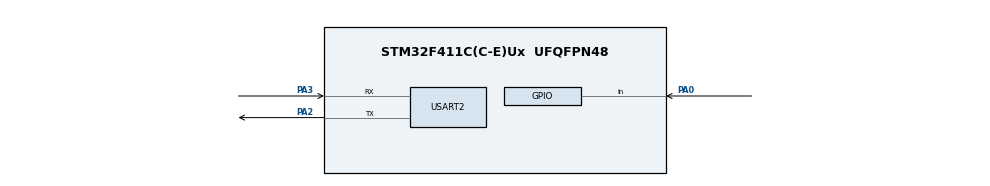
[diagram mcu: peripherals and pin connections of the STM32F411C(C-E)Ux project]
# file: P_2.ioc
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Mcu.Family=STM32F4
Mcu.Name=STM32F411C(C-E)Ux
Mcu.Package=UFQFPN48
NVIC.PriorityGroup=NVIC_PRIORITYGROUP_4
PA0-WKUP.GPIO_PuPd=GPIO_PULLUP
PA0-WKUP.Signal=GPIO_Input
PA13.Mode=Serial_Wire
PA13.Signal=SYS_JTMS-SWDIO
PA14.Mode=Serial_Wire
PA14.Signal=SYS_JTCK-SWCLK
PA2.Mode=Asynchronous
PA2.Signal=USART2_TX
PA3.Mode=Asynchronous
PA3.Signal=USART2_RX
ProjectManager.HeapSize=0x200
ProjectManager.StackSize=0x400
ProjectManager.TargetToolchain=STM32CubeIDE
RCC.AHBFreq_Value=16000000
RCC.APB1Freq_Value=16000000
RCC.APB2Freq_Value=16000000
RCC.CortexFreq_Value=16000000
RCC.HSE_VALUE=25000000
RCC.HSI_VALUE=16000000
RCC.LSE_VALUE=32768
RCC.SYSCLKFreq_VALUE=16000000
RCC.VCOOutputFreq_Value=192000000
USART2.VirtualMode=VM_ASYNC
VP_CRC_VS_CRC.Mode=CRC_Activate
board=custom

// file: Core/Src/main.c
/* USER CODE BEGIN Header */
/**
  ******************************************************************************
  * @file           : main.c
  * @brief          : Main program body
  ******************************************************************************
  * @attention
  *
  * Copyright (c) 2025 STMicroelectronics.
  * All rights reserved.
  *
  * This software is licensed under terms that can be found in the LICENSE file
  * in the root directory of this software component.
  * If no LICENSE file comes with this software, it is provided AS-IS.
  *
  ******************************************************************************
  */
/* USER CODE END Header */
#include "main.h"

CRC_HandleTypeDef hcrc;

UART_HandleTypeDef huart2;

/* USER CODE BEGIN PV */
#define C_UART			huart2

uint8_t bl_rx_buffer[200];
uint8_t supported_commands[10] = {BL_GET_VER, BL_GET_HELP, BL_GET_CID, BL_GET_RDP_STATUS, BL_GO_TO_ADDR,BL_FLASH_ERASE,
		BL_MEM_WRITE, BL_EN_RW_PROTECT, BL_MEM_READ, BL_READ_SECTOR_P_STATUS, BL_OTP_READ, BL_DIS_R_W_PROTECT};
/* USER CODE END PV */

void SystemClock_Config(void);
static void MX_GPIO_Init(void);
static void MX_USART2_UART_Init(void);
static void MX_CRC_Init(void);
/* USER CODE BEGIN PFP */
static void printmsg(char *format,...);
static void bootloader_send_ack(uint8_t command_code, uint8_t follow_len);
static void bootloader_send_nack(void);
uint8_t bootloader_verify_crc (uint8_t *pData, uint32_t len, uint32_t crc_host);
static uint8_t get_bootloader_version(void);
static void bootloader_uart_write_data(uint8_t *pBuffer,uint32_t len);
uint16_t get_mcu_device_id(void);
uint8_t get_flash_rdp_level(void);
uint8_t verify_addr(uint32_t addr);
uint8_t execute_flash_erase(uint8_t sector_number , uint8_t number_of_sector);
uint8_t program_memory(uint8_t *pBuffer, uint32_t base_mem_addr, uint8_t payload_length);
uint8_t configure_protection(uint8_t protection, uint8_t sector_detail, uint8_t disable);
void read_protection_status(uint8_t *sector_detail);
/* USER CODE END PFP */

int main(void)
{

  /* USER CODE BEGIN 1 */
#define BL_DEBUG_MSG_EN		1
  /* USER CODE END 1 */

  /* MCU Configuration--------------------------------------------------------*/

  /* Reset of all peripherals, Initializes the Flash interface and the Systick. */
  HAL_Init();

  /* Configure the system clock */
  SystemClock_Config();

  /* Initialize all configured peripherals */
  MX_GPIO_Init();
  MX_USART2_UART_Init();
  MX_CRC_Init();

  /* Infinite loop */
  while (1)
  {

    /* USER CODE BEGIN 3 */
	  if(HAL_GPIO_ReadPin(GPIOA, GPIO_PIN_0) == 1)
	    {
	  	  // button is pressed
	  	  printmsg("BL_DEBUG_MSG:Button is pressed .. going to BL mode \r\n");

	  	  bootloader_uart_read_data();
	    }
	    else
	    {
	  	printmsg("BL_DEBUG_MSG:Button is not pressed .. executing user app\r\n");
	  	 bootloader_jump_to_user_app();
	    }
  }
  /* USER CODE END 3 */
}

void SystemClock_Config(void)
{
    RCC_OscInitTypeDef RCC_OscInitStruct = {0};
    RCC_ClkInitTypeDef RCC_ClkInitStruct = {0};

    /** Configure the main internal regulator output voltage */
    __HAL_RCC_PWR_CLK_ENABLE();
    __HAL_PWR_VOLTAGESCALING_CONFIG(PWR_REGULATOR_VOLTAGE_SCALE1);

    /** Initializes the RCC Oscillators according to the specified parameters */
    RCC_OscInitStruct.OscillatorType = RCC_OSCILLATORTYPE_HSE;
    RCC_OscInitStruct.HSEState = RCC_HSE_ON;               // ✅ Enable external 25 MHz crystal
    RCC_OscInitStruct.PLL.PLLState = RCC_PLL_ON;           // ✅ Enable PLL
    RCC_OscInitStruct.PLL.PLLSource = RCC_PLLSOURCE_HSE;   // ✅ Source = HSE
    RCC_OscInitStruct.PLL.PLLM = 25;                       // Divide 25 MHz → 1 MHz
    RCC_OscInitStruct.PLL.PLLN = 100;                      // Multiply 1 MHz → 100 MHz
    RCC_OscInitStruct.PLL.PLLP = RCC_PLLP_DIV2;            // 100 MHz / 2 = 100 MHz SYSCLK
    RCC_OscInitStruct.PLL.PLLQ = 4;                        // Optional (USB clock etc.)

    if (HAL_RCC_OscConfig(&RCC_OscInitStruct) != HAL_OK)
    {
        Error_Handler();
    }

    /** Initializes the CPU, AHB and APB buses clocks */
    RCC_ClkInitStruct.ClockType = RCC_CLOCKTYPE_HCLK |
                                  RCC_CLOCKTYPE_SYSCLK |
                                  RCC_CLOCKTYPE_PCLK1 |
                                  RCC_CLOCKTYPE_PCLK2;

    RCC_ClkInitStruct.SYSCLKSource = RCC_SYSCLKSOURCE_PLLCLK;  // ✅ Use PLL as system clock
    RCC_ClkInitStruct.AHBCLKDivider = RCC_SYSCLK_DIV1;         // AHB = 100 MHz
    RCC_ClkInitStruct.APB1CLKDivider = RCC_HCLK_DIV2;          // APB1 = 50 MHz (max)
    RCC_ClkInitStruct.APB2CLKDivider = RCC_HCLK_DIV1;          // APB2 = 100 MHz

    if (HAL_RCC_ClockConfig(&RCC_ClkInitStruct, FLASH_LATENCY_3) != HAL_OK)
    {
        Error_Handler();
    }
}

static void MX_CRC_Init(void)
{

  hcrc.Instance = CRC;
  if (HAL_CRC_Init(&hcrc) != HAL_OK)
  {
    Error_Handler();
  }

}

static void MX_USART2_UART_Init(void)
{

  huart2.Instance = USART2;
  huart2.Init.BaudRate = 9600;
  huart2.Init.WordLength = UART_WORDLENGTH_8B;
  huart2.Init.StopBits = UART_STOPBITS_1;
  huart2.Init.Parity = UART_PARITY_NONE;
  huart2.Init.Mode = UART_MODE_TX_RX;
  huart2.Init.HwFlowCtl = UART_HWCONTROL_NONE;
  huart2.Init.OverSampling = UART_OVERSAMPLING_16;
  if (HAL_UART_Init(&huart2) != HAL_OK)
  {
    Error_Handler();
  }

}

static void MX_GPIO_Init(void)
{
  GPIO_InitTypeDef GPIO_InitStruct = {0};

  /* GPIO Ports Clock Enable */
  __HAL_RCC_GPIOA_CLK_ENABLE();

  /*Configure GPIO pin : PA0 */
  GPIO_InitStruct.Pin = GPIO_PIN_0;
  GPIO_InitStruct.Mode = GPIO_MODE_INPUT;
  GPIO_InitStruct.Pull = GPIO_PULLUP;
  HAL_GPIO_Init(GPIOA, &GPIO_InitStruct);

}

/* USER CODE BEGIN 4 */
static void printmsg(char *format,...)
{
#ifdef BL_DEBUG_MSG_EN
	char str[80];

	va_list args;
	va_start(args, format);
	vsprintf(str, format, args);
	printf(str);
	//HAL_UART_Transmit(&huart2, (uint8_t*)str, strlen(str), HAL_MAX_DELAY);
	va_end(args);
#endif
}

void bootloader_uart_read_data(void)
{
	uint8_t rcv_len;
	memset(bl_rx_buffer, 0, 200);

	HAL_UART_Receive(&C_UART, bl_rx_buffer, 1, HAL_MAX_DELAY);
	rcv_len = bl_rx_buffer[0];
	HAL_UART_Receive(&C_UART, &bl_rx_buffer[1], rcv_len, HAL_MAX_DELAY);
	switch(bl_rx_buffer[1])
	{
		 case BL_GET_VER:
	          bootloader_handle_getver_cmd(bl_rx_buffer);
	          break;
	      case BL_GET_HELP:
	          bootloader_handle_gethelp_cmd(bl_rx_buffer);
	          break;
	      case BL_GET_CID:
	          bootloader_handle_getcid_cmd(bl_rx_buffer);
	          break;
	      case BL_GET_RDP_STATUS:
	          bootloader_handle_getrdp_cmd(bl_rx_buffer);
	          break;
	      case BL_GO_TO_ADDR:
	          bootloader_handle_go_cmd(bl_rx_buffer);
	          break;
	      case BL_FLASH_ERASE:
	          bootloader_handle_flash_erase_cmd(bl_rx_buffer);
	          break;
	      case BL_MEM_WRITE:
	          bootloader_handle_mem_write_cmd(bl_rx_buffer);
	          break;
	      case BL_EN_RW_PROTECT:
	          bootloader_handle_en_rw_protect(bl_rx_buffer);
	          break;
	      case BL_MEM_READ:
	          bootloader_handle_mem_read(bl_rx_buffer);
	          break;
	      case BL_READ_SECTOR_P_STATUS:
	          bootloader_handle_read_sector_protection_status(bl_rx_buffer);
	          break;
	      case BL_OTP_READ:
	          bootloader_handle_read_otp(bl_rx_buffer);
	          break;
	      case BL_DIS_R_W_PROTECT:
	          bootloader_handle_dis_rw_protect(bl_rx_buffer);
	          break;
	       default:
	          printmsg("BL_DEBUG_MSG:Invalid command code received from host \n");
	          break;
	}

}

void bootloader_jump_to_user_app(void)
{

	__disable_irq();

	// Disable SysTick
	SysTick->CTRL = 0;
	SysTick->VAL  = 0;

	// Disable UART fully
	__HAL_UART_DISABLE(&huart2);
	USART2->CR1 = 0;
	USART2->CR2 = 0;
	USART2->CR3 = 0;
	USART2->SR  = 0;
	USART2->DR  = 0;

	// Disable UART NVIC line
	NVIC_DisableIRQ(USART2_IRQn);

	// Clear ALL pending interrupts
	for(int i = 0; i < 8; i++)
	    NVIC->ICPR[i] = 0xFFFFFFFF;

	// Load MSP
	__set_MSP(*(uint32_t*)FLASH_SECTOR2_BASE_ADDRESS);

	// Fix Thumb-bit
	uint32_t resetHandler = (*(uint32_t*)(FLASH_SECTOR2_BASE_ADDRESS + 4)) | 1;

	// Set VTOR
	SCB->VTOR = FLASH_SECTOR2_BASE_ADDRESS;

	__DSB();
	__ISB();

	__enable_irq();

	// Jump
	((void (*)(void))resetHandler)();

}

void HAL_GPIO_EXTI_Callback(uint16_t GPIO_Pin)
{
	printmsg("BL_DEBUG_MSG:Button is pressed .. going to BL mode \r\n");

}

void bootloader_handle_getver_cmd(uint8_t *bl_rx_buffer)
{
	uint8_t bl_version;
	//1. Verify the checksum(CRC)
	printmsg("BL_DEBUG_MSG:bootloader handler getver cmd\n");
	 // 1) verify the checksum
	  printmsg("BL_DEBUG_MSG:bootloader_handle_getver_cmd\n");

	  //Total length of the command packet
	  uint32_t command_packet_len = bl_rx_buffer[0]+1 ;

	  //extract the CRC32 sent by the Host
	  uint32_t host_crc = *((uint32_t * ) (bl_rx_buffer+command_packet_len - 4) ) ;

	if(! bootloader_verify_crc(&bl_rx_buffer[0], 2, host_crc))
	{
		printmsg("BL_DEBUG_MSG:checksum success !!\n");
		//checksum is correct..
		bootloader_send_ack(bl_rx_buffer[0],1);
		bl_version = get_bootloader_version();
		printmsg("BL_DEBUG_MSG:BL_VER: %d %#\n", bl_version, bl_version);
		bootloader_uart_write_data(&bl_version, 1);
	}else
	{
		printmsg("BL_DEBUS_MSG:checksum fail !!\n");
		//checksum is wrong send nack
		bootloader_send_nack();
	}

}
void bootloader_handle_gethelp_cmd(uint8_t *pBuffer)
{
	//1. Verify the checksum(CRC)
	printmsg("BL_DEBUG_MSG:bootloader handler gethelp cmd\n");
		//Total length of the command packet
	  uint32_t command_packet_len = bl_rx_buffer[0]+1 ;

	  //extract the CRC32 sent by the Host
	  uint32_t host_crc = *((uint32_t * ) (bl_rx_buffer+command_packet_len - 4) ) ;

	if(! bootloader_verify_crc(&pBuffer[0], 2, host_crc))
	{
		printmsg("BL_DEBUG_MSG:checksum success !!\n");
		//checksum is correct..
		bootloader_send_ack(bl_rx_buffer[0],sizeof(supported_commands));
		bootloader_uart_write_data(supported_commands, sizeof(supported_commands));
	}else
	{
		printmsg("BL_DEBUS_MSG:checksum fail !!\n");
		//checksum is wrong send nack
		bootloader_send_nack();
	}

}
void bootloader_handle_getcid_cmd(uint8_t *pBuffer)
{
	uint16_t cid = get_mcu_device_id();
	//1. Verify the checksum(CRC)
		printmsg("BL_DEBUG_MSG:bootloader handler getcid cmd\n");
			//Total length of the command packet
		  uint32_t command_packet_len = bl_rx_buffer[0]+1 ;

		  //extract the CRC32 sent by the Host
		  uint32_t host_crc = *((uint32_t * ) (bl_rx_buffer+command_packet_len - 4) ) ;

		if(! bootloader_verify_crc(&pBuffer[0], 2, host_crc))
		{
			printmsg("BL_DEBUG_MSG:checksum success !!\n");
			//checksum is correct..

			bootloader_send_ack(bl_rx_buffer[0],sizeof(cid));
			bootloader_uart_write_data((uint8_t*)&cid, 2);
		}else
		{
			printmsg("BL_DEBUS_MSG:checksum fail !!\n");
			//checksum is wrong send nack
			bootloader_send_nack();
		}

}
void bootloader_handle_getrdp_cmd(uint8_t *pBuffer)
{
	uint8_t rdp_status = get_flash_rdp_level();
	//1. Verify the checksum(CRC)
		printmsg("BL_DEBUG_MSG:bootloader handler getrdp cmd\n");
			//Total length of the command packet
		  uint32_t command_packet_len = bl_rx_buffer[0]+1 ;

		  //extract the CRC32 sent by the Host
		  uint32_t host_crc = *((uint32_t * ) (bl_rx_buffer+command_packet_len - 4) ) ;

		if(! bootloader_verify_crc(&pBuffer[0], 2, host_crc))
		{
			printmsg("BL_DEBUG_MSG:checksum success !!\n");
			//checksum is correct..

			bootloader_send_ack(bl_rx_buffer[0],sizeof(rdp_status));
			bootloader_uart_write_data((uint8_t*)&rdp_status, 1);
		}else
		{
			printmsg("BL_DEBUS_MSG:checksum fail !!\n");
			//checksum is wrong send nack
			bootloader_send_nack();
		}

}
void bootloader_handle_go_cmd(uint8_t *pBuffer)
{
	uint32_t go_addr = 0;
	uint8_t addr_valid = ADDR_VALID;
	uint8_t addr_invalid = ADDR_INVALID;
	//1. Verify the checksum(CRC)
		printmsg("BL_DEBUG_MSG:bootloader handler go_cmd cmd\n");
			//Total length of the command packet
		  uint32_t command_packet_len = bl_rx_buffer[0]+1 ;

		  //extract the CRC32 sent by the Host
		  uint32_t host_crc = *((uint32_t * ) (bl_rx_buffer+command_packet_len - 4) ) ;

		if(! bootloader_verify_crc(&pBuffer[0], command_packet_len - 4, host_crc))
		{
			printmsg("BL_DEBUG_MSG:checksum success !!\n");
			//checksum is correct..

			bootloader_send_ack(bl_rx_buffer[0],1);

			//etract the go address
			go_addr = *((uint32_t*)&pBuffer[2]);
			if(verify_addr(go_addr) == ADDR_VALID)
			{
				// tell host that address is find
				bootloader_uart_write_data(&addr_valid, 1);
				if(go_addr != 0x08008000)
				{
					go_addr += 1; // for T bit
					void(*lets_jump)(void) = (void*)go_addr;
					printmsg("BL_DEBUG_MSG: jumping to the address\n");
					lets_jump();
				}
				else
				{
					bootloader_jump_to_user_app();
				}

			}
			else
			{
				printmsg("BL_DEBUS_MSG: invalid address\n");
				bootloader_uart_write_data(&addr_invalid, 1);
			}

		}else
		{
			printmsg("BL_DEBUS_MSG:checksum fail !!\n");
			//checksum is wrong send nack
			bootloader_send_nack();
		}

}
void bootloader_handle_flash_erase_cmd(uint8_t *pBuffer)
{
	uint8_t sector_addr = 0;

	uint8_t no_of_sectors = 0;
	uint8_t erase_status = 0x00;
	//1. Verify the checksum(CRC)
		printmsg("BL_DEBUG_MSG:bootloader handler flash_erase_cmd\n");
			//Total length of the command packet
		  uint32_t command_packet_len = bl_rx_buffer[0]+1 ;

		  //extract the CRC32 sent by the Host
		  uint32_t host_crc = *((uint32_t * ) (bl_rx_buffer+command_packet_len - 4) ) ;

		if(! bootloader_verify_crc(&pBuffer[0], command_packet_len - 4, host_crc))
		{
			printmsg("BL_DEBUG_MSG:checksum success !!\n");
			//checksum is correct..

			bootloader_send_ack(bl_rx_buffer[0],1);

			sector_addr = *((uint32_t*)&pBuffer[2]);
			no_of_sectors = *((uint32_t*)&pBuffer[3]);

			erase_status = execute_flash_erase(sector_addr, no_of_sectors);
			bootloader_uart_write_data(&erase_status,1);

		}else
		{
			printmsg("BL_DEBUS_MSG:checksum fail !!\n");
			//checksum is wrong send nack
			bootloader_send_nack();
		}

}
void bootloader_handle_mem_write_cmd(uint8_t *pBuffer)
{
	uint8_t payload_length = 0;
	uint32_t base_mem_addr = 0;
	uint8_t addr_valid = ADDR_VALID;
	uint8_t addr_invalid = ADDR_INVALID;
	//1. Verify the checksum(CRC)
		printmsg("BL_DEBUG_MSG:bootloader handler mem_write_cmd\n");
			//Total length of the command packet
		  uint32_t command_packet_len = bl_rx_buffer[0]+1 ;

		  //extract the CRC32 sent by the Host
		  uint32_t host_crc = *((uint32_t * ) (bl_rx_buffer+command_packet_len - 4) ) ;

		if(! bootloader_verify_crc(&pBuffer[0], command_packet_len - 4, host_crc))
		{
			printmsg("BL_DEBUG_MSG:checksum success !!\n");
			//checksum is correct..

			bootloader_send_ack(bl_rx_buffer[0],1);

			//etract the go address
			base_mem_addr = *((uint32_t*)&pBuffer[2]);
			payload_length = pBuffer[6];

			if(verify_addr(base_mem_addr) == ADDR_VALID)
			{
				// tell host that address is find
				bootloader_uart_write_data(&addr_valid, 1);
				program_memory(pBuffer, base_mem_addr, payload_length);

			}
			else
			{
				printmsg("BL_DEBUS_MSG: invalid address\n");
				bootloader_uart_write_data(&addr_invalid, 1);
			}

		}else
		{
			printmsg("BL_DEBUS_MSG:checksum fail !!\n");
			//checksum is wrong send nack
			bootloader_send_nack();
		}
}
void bootloader_handle_en_rw_protect(uint8_t *pBuffer)
{
	uint8_t sector_detail = 0;
	uint8_t protection = 0;
	uint8_t status = HAL_OK;

	//1. Verify the checksum(CRC)
		printmsg("BL_DEBUG_MSG:bootloader handler en_rw_protect_cmd\n");
			//Total length of the command packet
		  uint32_t command_packet_len = bl_rx_buffer[0]+1 ;

		  //extract the CRC32 sent by the Host
		  uint32_t host_crc = *((uint32_t * ) (bl_rx_buffer+command_packet_len - 4) ) ;

		if(! bootloader_verify_crc(&pBuffer[0], command_packet_len - 4, host_crc))
		{
			printmsg("BL_DEBUG_MSG:checksum success !!\n");
			//checksum is correct..

			bootloader_send_ack(bl_rx_buffer[0],1);

			//etract the go address
			sector_detail = pBuffer[2];
			protection = pBuffer[3];
			status = configure_protection(protection, sector_detail, 0);
			bootloader_uart_write_data(&status,1);

		}else
		{
			printmsg("BL_DEBUS_MSG:checksum fail !!\n");
			//checksum is wrong send nack
			bootloader_send_nack();
		}
}
void bootloader_handle_mem_read (uint8_t *pBuffer)
{

}
void bootloader_handle_read_sector_protection_status(uint8_t *pBuffer)
{
	uint8_t sector_detail[2];

	//1. Verify the checksum(CRC)
		printmsg("BL_DEBUG_MSG:bootloader handler read_rw_protect_cmd\n");
			//Total length of the command packet
		  uint32_t command_packet_len = bl_rx_buffer[0]+1 ;

		  //extract the CRC32 sent by the Host
		  uint32_t host_crc = *((uint32_t * ) (bl_rx_buffer+command_packet_len - 4) ) ;

		if(! bootloader_verify_crc(&pBuffer[0], command_packet_len - 4, host_crc))
		{
			printmsg("BL_DEBUG_MSG:checksum success !!\n");
			//checksum is correct..

			bootloader_send_ack(bl_rx_buffer[0],1);

			//etract the go address
			read_protection_status(sector_detail);
			bootloader_uart_write_data(sector_detail,2);

		}else
		{
			printmsg("BL_DEBUS_MSG:checksum fail !!\n");
			//checksum is wrong send nack
			bootloader_send_nack();
		}

}
void bootloader_handle_read_otp(uint8_t *pBuffer)
{

}
void bootloader_handle_dis_rw_protect(uint8_t *pBuffer)
{
	uint8_t status = HAL_OK;
	//1. Verify the checksum(CRC)
		printmsg("BL_DEBUG_MSG:bootloader handler dis_rw_protect_cmd\n");
			//Total length of the command packet
		  uint32_t command_packet_len = bl_rx_buffer[0]+1 ;

		  //extract the CRC32 sent by the Host
		  uint32_t host_crc = *((uint32_t * ) (bl_rx_buffer+command_packet_len - 4) ) ;

		if(! bootloader_verify_crc(&pBuffer[0], command_packet_len - 4, host_crc))
		{
			printmsg("BL_DEBUG_MSG:checksum success !!\n");
			//checksum is correct..

			bootloader_send_ack(bl_rx_buffer[0],1);

			//etract the go address
			status = configure_protection(0, 0, 1);
			bootloader_uart_write_data(&status,1);

		}else
		{
			printmsg("BL_DEBUS_MSG:checksum fail !!\n");
			//checksum is wrong send nack
			bootloader_send_nack();
		}
}

// helper funcitons
static void bootloader_send_ack(uint8_t command_code, uint8_t follow_len)
{
	//here we send 2 byte.. first byte is ack and the second bytes is len value
	uint8_t ack_buf[2];
	ack_buf[0] = BL_ACK;
	ack_buf[1] = follow_len;
	HAL_UART_Transmit(&C_UART, ack_buf, 2, HAL_MAX_DELAY);
}
static void bootloader_send_nack(void)
{
	uint8_t nack = BL_NACK;
	HAL_UART_Transmit(&C_UART, &nack, 1, HAL_MAX_DELAY);
}

static uint8_t get_bootloader_version(void)
{
	uint8_t ver = BL_VERSION;
	return ver;
}

uint8_t bootloader_verify_crc (uint8_t *pData, uint32_t len, uint32_t crc_host)
{

		uint32_t uwCRCValue;
		CRC->CR |= CRC_CR_RESET;

		for (uint32_t i=0 ; i < len ; i++) {

		uint32_t i_data = pData[i];
		uwCRCValue = HAL_CRC_Accumulate(&hcrc, &i_data, 1);
		}

//	    uint32_t data_word = 0;
//	    for(uint32_t i = 0; i < len; i++)
//	    {
//	    data_word |= ((uint32_t)pData[i]) << (i*8);
//	    }
//
//	    // Compute CRC of exactly one word
//	    uwCRCValue = HAL_CRC_Calculate(&hcrc, &data_word, 1);
		if( uwCRCValue == crc_host) {

		return VERIFY_CRC_SUCCESS;
		}

		return VERIFY_CRC_FAIL;
}

static void bootloader_uart_write_data(uint8_t *pBuffer,uint32_t len) {

  /*you can replace the below ST's USART driver API call with your MCUs driver API call */
  HAL_UART_Transmit(&C_UART,pBuffer,len,HAL_MAX_DELAY);

}
uint16_t get_mcu_device_id(void)
{
	uint16_t id = (uint16_t)DBGMCU->IDCODE;
	return (id & 0x0FFF);
}

uint8_t get_flash_rdp_level(void)
{
	volatile uint32_t *pob_addr = (uint32_t*)0x1FFFC000;
	uint8_t rdp_status = (uint8_t)(*(pob_addr) >> 8);
	return rdp_status;
}
uint8_t verify_addr(uint32_t addr)
{
	if(addr >= SRAM1_BASE && addr <= 0x20020000)
	{
		return ADDR_VALID;
	}
//	if(addr >= SRAM2_BASE && addr <= SRAM2_END)
//	{
//		return ADDR_VALID;
//	}
	if(addr >= FLASH_BASE && addr <= FLASH_END)
		{
			return ADDR_VALID;
		}
//	if(addr >= BKPSRAM_BB_BASE && addr <= BKPSRAM_END) No backup SRAM in yours
//		{
//			return ADDR_VALID;
//		}
	else
	{
		return ADDR_INVALID;
	}
}

uint8_t execute_flash_erase(uint8_t sector_number , uint8_t number_of_sector)
{

  //we have totally 8 sectors in STM32F446RE mcu .. sector[0 to 7]
  //number_of_sector has to be in the range of 0 to 7
  // if sector_number = 0xff , that means mass erase !
  //Code needs to modified if your MCU supports more flash sectors
  FLASH_EraseInitTypeDef flashErase_handle;
  uint32_t sectorError;
  HAL_StatusTypeDef status;

  if( number_of_sector > 8 )
    return INVALID_SECTOR;

  if( (sector_number == 0xff ) || (sector_number <= 7) ) {
    if(sector_number == (uint8_t) 0xff) {
    flashErase_handle.TypeErase = FLASH_TYPEERASE_MASSERASE;

    } else {
      /*Here we are just calculating how many sectors needs to erased */
      uint8_t remanining_sector = 8 - sector_number;
      if( number_of_sector > remanining_sector) {

        number_of_sector = remanining_sector;
      }
      flashErase_handle.TypeErase = FLASH_TYPEERASE_SECTORS;
      flashErase_handle.Sector = sector_number; // this is the initial sector
      flashErase_handle.NbSectors = number_of_sector;
    }
    flashErase_handle.Banks = FLASH_BANK_1;

    /*Get access to touch the flash registers */
    HAL_FLASH_Unlock();
    flashErase_handle.VoltageRange = FLASH_VOLTAGE_RANGE_3;  // our mcu will work on this voltage range
    status = (uint8_t) HAL_FLASHEx_Erase(&flashErase_handle, &sectorError);
    HAL_FLASH_Lock();

    return status;
  }

  return INVALID_SECTOR;
}

uint8_t program_memory(uint8_t *pBuffer, uint32_t base_mem_addr, uint8_t payload_length)
{
	uint8_t status = HAL_OK;
	HAL_FLASH_Unlock();

	for(uint8_t i = 0; i <= payload_length; i++)
	{
		status = HAL_FLASH_Program(FLASH_TYPEPROGRAM_BYTE, base_mem_addr + i, pBuffer[i]);
	}

	HAL_FLASH_Lock();
	return status;
}

uint8_t configure_protection(uint8_t protection, uint8_t sector_detail, uint8_t disable)
{

	uint8_t status = HAL_OK;
	uint32_t *pOPTCR = (uint32_t*) 0x40023C14;

	if(disable == 0)
	{
		HAL_FLASH_OB_Unlock();
		while(__HAL_FLASH_GET_FLAG(FLASH_FLAG_BSY) != RESET);
		if(protection == 1) //means you are enabling the protection
		{
			*pOPTCR &= ~(1 << 31);
			*pOPTCR &= ~(sector_detail << 16);
		}
		else
		{
			*pOPTCR |= (1 << 31);
		    *pOPTCR &= ~(0xff << 16);
		    *pOPTCR |= (sector_detail << 16);
		}
		// set the option start bit(otpstart)
		*pOPTCR |= (1 << 1);
		while(__HAL_FLASH_GET_FLAG(FLASH_FLAG_BSY) != RESET);
		status = HAL_FLASH_OB_Lock();
	}
	else
	{
		HAL_FLASH_OB_Unlock();
		while(__HAL_FLASH_GET_FLAG(FLASH_FLAG_BSY) != RESET);
		*pOPTCR &= ~(1 << 31);
		*pOPTCR |= (0xFF << 16) ;
		// set the option start bit(otpstart)
		*pOPTCR |= (1 << 1);
		while(__HAL_FLASH_GET_FLAG(FLASH_FLAG_BSY) != RESET);
		status = HAL_FLASH_OB_Lock();

	}
	return status;
}

void read_protection_status(uint8_t *sector_detail)
{
	uint32_t *pOPTCR = (uint32_t*) 0x40023C14;
	uint32_t optcr = *pOPTCR;
	sector_detail[0] = (uint8_t)((optcr & (0xFF << 16)) >> 16); // for nWRP
	sector_detail[1] = (uint8_t)(optcr & (1 << 31)); // for sprmod
}

/* USER CODE END 4 */

void Error_Handler(void)
{
  __disable_irq();
  while (1)
  {
  }
}
